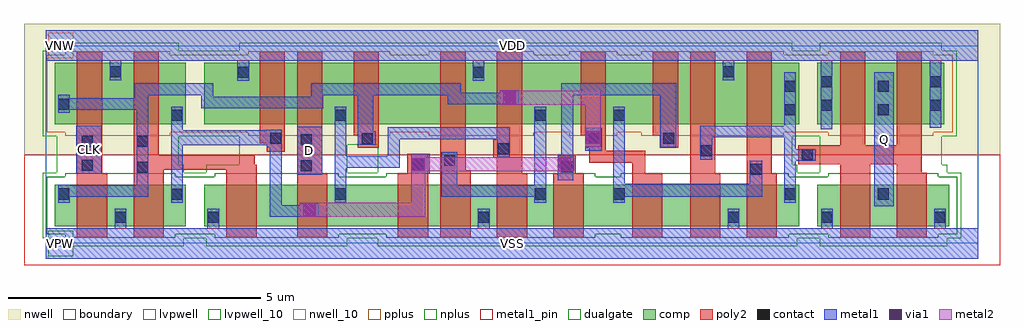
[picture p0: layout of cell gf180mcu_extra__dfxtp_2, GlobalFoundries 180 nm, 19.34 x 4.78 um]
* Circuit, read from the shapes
.subckt gf180mcu_extra__dfxtp_2 CLK D Q VDD VNW VSS
XM1 VSS CLK n1 VSUBS nfet_06v0 w=0.82u l=0.6u
XM2 n2 n1 VSS VSUBS nfet_06v0 w=0.82u l=0.6u
XM3 n3 n1 VSS VSUBS nfet_06v0 w=0.82u l=0.6u
XM4 n4 D n3 VSUBS nfet_06v0 w=0.82u l=0.6u
XM5 n5 n2 n4 VSUBS nfet_06v0 w=0.82u l=0.6u
XM6 VSS n6 n5 VSUBS nfet_06v0 w=0.82u l=0.6u
XM7 n6 n4 VSS VSUBS nfet_06v0 w=0.82u l=0.6u
XM8 n7 n2 n6 VSUBS nfet_06v0 w=0.82u l=0.6u
XM9 n8 n1 n7 VSUBS nfet_06v0 w=0.82u l=0.6u
XM10 VSS n9 n8 VSUBS nfet_06v0 w=0.82u l=0.6u
XM11 n9 n7 VSS VSUBS nfet_06v0 w=0.82u l=0.6u
XM12 Q n9 VSS VSUBS nfet_06v0 w=0.82u l=0.6u m=2
XM13 VDD CLK n1 VNW pfet_06v0 w=1.22u l=0.5u
XM14 n2 n1 VDD VNW pfet_06v0 w=1.22u l=0.5u
XM15 n10 n2 VDD VNW pfet_06v0 w=1.22u l=0.5u
XM16 n4 D n10 VNW pfet_06v0 w=1.22u l=0.5u
XM17 n11 n1 n4 VNW pfet_06v0 w=1.22u l=0.5u
XM18 VDD n6 n11 VNW pfet_06v0 w=1.22u l=0.5u
XM19 n6 n4 VDD VNW pfet_06v0 w=1.22u l=0.5u
XM20 n7 n1 n6 VNW pfet_06v0 w=1.22u l=0.5u
XM21 n12 n2 n7 VNW pfet_06v0 w=1.22u l=0.5u
XM22 VDD n9 n12 VNW pfet_06v0 w=1.22u l=0.5u
XM23 n9 n7 VDD VNW pfet_06v0 w=1.22u l=0.5u
XM24 Q n9 VDD VNW pfet_06v0 w=1.22u l=0.5u m=2
.ends

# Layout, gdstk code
import gdstk
lib = gdstk.Library(unit=1e-6, precision=1e-09)
def R(c, l, rs):  # rectangles x0, y0, x1, y1
    for r in rs: c.add(gdstk.rectangle(r[:2], r[2:], *l))
boundary = (0, 0)
nwell = (21, 0)
nwell_10 = (21, 10)
comp = (22, 0)
poly2 = (30, 0)
pplus = (31, 0)
nplus = (32, 0)
contact = (33, 0)
metal1 = (34, 0)
metal1_pin = (34, 10)
via1 = (35, 0)
metal2 = (36, 0)
dualgate = (55, 0)
lvpwell = (204, 0)
lvpwell_10 = (204, 10)

gf180mcu_extra__dfxtp_2 = lib.new_cell('gf180mcu_extra__dfxtp_2')
R(gf180mcu_extra__dfxtp_2, boundary, [(0,0,18.48,3.92)])
R(gf180mcu_extra__dfxtp_2, nwell, [(-0.43,1.76,18.91,4.35)])
R(gf180mcu_extra__dfxtp_2, nwell_10, [(0.05,3.67,0.55,4.17)])
R(gf180mcu_extra__dfxtp_2, comp, [(0.18,0.34,2.78,1.16), (3.14,0.34,14.93,1.16), (15.29,0.34,17.9,1.16), (0.18,2.36,2.78,3.58), (3.14,2.36,14.93,3.58), (15.29,2.36,17.81,3.58)])
R(gf180mcu_extra__dfxtp_2, poly2, [(0.62,0.12,1.22,1.38), (1.74,0.12,2.34,1.46), (3.58,0.12,4.18,1.46), (4.98,0.12,5.58,1.38), (6.98,0.12,7.58,1.38), (7.82,0.12,8.42,1.445), (8.94,0.12,9.54,1.38), (10.06,0.12,10.66,1.38), (11.62,0.12,12.22,1.38), (12.77,0.12,13.37,1.38), (13.89,0.12,14.49,1.385), (15.74,0.12,16.34,1.565), (16.86,0.12,17.46,1.4), (0.62,1.38,1.12,3.8), (4.98,1.38,5.48,3.8), (7.165,1.38,7.58,1.78), (8.94,1.38,9.44,1.695), (10.145,1.38,10.505,1.74), (11.62,1.38,11.88,1.595), (12.77,1.38,13.27,3.8), (13.89,1.385,14.39,3.8), (16.86,1.4,17.36,1.565), (7.82,1.445,8.32,3.8), (1.74,1.46,4.18,1.555), (1.74,1.555,4.145,1.745), (14.91,1.565,17.36,1.95), (10.775,1.595,11.88,1.835), (8.87,1.695,9.44,2.06), (1.74,1.745,2.24,3.8), (4.38,1.82,4.74,1.985), (10.775,1.835,11.1,1.9), (6.185,1.895,6.6,2.14), (10.695,1.9,11.1,2.14), (12.17,1.9,12.53,2.14), (15.74,1.95,16.24,3.8), (16.86,1.95,17.36,3.8), (4.24,1.985,4.74,3.8), (8.94,2.06,9.44,3.8), (6.1,2.14,6.6,3.8), (10.6,2.14,11.1,3.8), (12.03,2.14,12.53,3.8)])
R(gf180mcu_extra__dfxtp_2, pplus, [(0.39,2.13,2.47,2.2), (4.01,2.13,6.83,2.2), (7.59,2.13,9.67,2.2), (10.37,2.13,11.33,2.2), (11.8,2.13,14.62,2.2), (15.51,2.13,17.59,2.2), (0.02,2.2,17.97,3.74), (0.39,3.74,2.47,3.81), (4.01,3.74,6.83,3.81), (7.59,3.74,9.67,3.81), (10.37,3.74,11.33,3.81), (11.8,3.74,14.62,3.81), (15.51,3.74,17.59,3.81)])
R(gf180mcu_extra__dfxtp_2, nplus, [(0.39,0.11,2.57,0.18), (3.35,0.11,5.81,0.18), (6.75,0.11,10.89,0.18), (11.39,0.11,14.72,0.18), (15.51,0.11,17.69,0.18), (0.02,0.18,18.06,1.32), (0.39,1.32,2.57,1.39), (3.35,1.32,5.81,1.39), (6.75,1.32,10.89,1.39), (11.39,1.32,14.72,1.39), (15.51,1.32,17.69,1.39)])
R(gf180mcu_extra__dfxtp_2, contact, [(1.37,0.41,1.59,0.63), (3.21,0.41,3.43,0.63), (8.57,0.41,8.79,0.63), (13.52,0.41,13.74,0.63), (15.37,0.41,15.59,0.63), (17.61,0.41,17.83,0.63), (2.49,0.865,2.71,1.085), (0.25,0.87,0.47,1.09), (5.73,0.87,5.95,1.09), (9.69,0.87,9.91,1.09), (11.25,0.87,11.47,1.09), (14.64,0.87,14.86,1.09), (16.49,0.87,16.71,1.09), (13.965,1.36,14.185,1.58), (1.81,1.4,2.03,1.62), (10.215,1.41,10.435,1.63), (5.05,1.43,5.27,1.65), (0.71,1.44,0.93,1.66), (7.265,1.45,7.485,1.67), (7.895,1.54,8.115,1.76), (14.98,1.645,15.2,1.865), (12.98,1.725,13.2,1.945), (8.96,1.765,9.18,1.985), (0.71,1.91,0.93,2.13), (1.81,1.915,2.03,2.135), (5.05,1.945,5.27,2.165), (6.26,1.965,6.48,2.185), (4.45,1.97,4.67,2.19), (10.765,1.97,10.985,2.19), (12.24,1.97,12.46,2.19), (2.49,2.43,2.71,2.65), (5.73,2.43,5.95,2.65), (9.69,2.43,9.91,2.65), (11.25,2.43,11.47,2.65), (14.64,2.535,14.86,2.755), (16.49,2.535,16.71,2.755), (15.36,2.625,15.58,2.845), (17.52,2.625,17.74,2.845), (0.25,2.65,0.47,2.87), (14.64,3.005,14.86,3.225), (16.49,3.005,16.71,3.225), (15.36,3.095,15.58,3.315), (17.52,3.095,17.74,3.315), (3.805,3.285,4.025,3.505), (8.47,3.285,8.69,3.505), (1.27,3.29,1.49,3.51), (13.42,3.29,13.64,3.51)])
R(gf180mcu_extra__dfxtp_2, metal1, [(0,-0.3,18.48,0.3), (1.365,0.3,1.595,0.69), (3.205,0.3,3.435,0.69), (8.565,0.3,8.795,0.69), (13.515,0.3,13.745,0.69), (15.365,0.3,15.595,0.69), (17.605,0.3,17.835,0.69), (4.435,0.53,5.41,0.76), (16.42,0.735,16.805,3.39), (4.435,0.76,4.675,1.91), (5.03,0.76,5.41,0.8), (2.485,0.805,2.715,1.95), (0.245,0.81,0.475,0.92), (5.725,0.81,5.955,1.5), (9.685,0.81,9.915,0.925), (11.245,0.81,11.475,0.92), (14.635,0.81,14.865,1.64), (0.245,0.92,2.035,1.15), (11.245,0.92,14.2,1.18), (7.84,0.925,9.915,1.155), (0.245,1.15,0.475,1.16), (1.805,1.15,2.035,2.645), (7.84,1.155,8.16,1.81), (9.685,1.155,9.915,2.71), (11.245,1.18,11.475,2.71), (13.955,1.18,14.2,1.64), (10.145,1.255,10.45,1.76), (4.98,1.365,5.48,2.315), (0.61,1.38,1.11,2.33), (7.245,1.38,7.61,1.78), (5.725,1.5,7.015,1.73), (14.635,1.64,15.26,1.87), (12.975,1.66,13.205,2.105), (8.95,1.705,9.195,2.065), (5.725,1.73,5.955,2.71), (6.775,1.73,7.015,2.065), (10.22,1.76,10.45,2.94), (10.695,1.84,11.015,2.295), (14.635,1.87,14.865,2.105), (4.38,1.91,4.675,1.95), (12.18,1.91,12.495,2.94), (2.485,1.95,4.675,2.245), (6.185,1.96,6.545,2.225), (6.775,2.065,9.195,2.3), (12.975,2.105,14.865,2.335), (6.185,2.225,6.49,2.94), (2.485,2.245,2.715,2.71), (4.38,2.245,4.675,2.25), (15.355,2.26,15.585,3.62), (17.515,2.29,17.745,3.62), (14.635,2.335,14.865,3.39), (0.245,2.59,0.475,2.645), (0.245,2.645,2.035,2.875), (3.085,2.675,5.495,2.905), (7.965,2.76,9.375,2.94), (0.245,2.875,0.475,2.95), (1.765,2.875,2.035,2.94), (3.085,2.905,3.325,2.94), (5.265,2.905,5.495,2.94), (1.765,2.94,3.325,3.17), (5.265,2.94,9.375,2.99), (10.22,2.94,12.495,3.17), (5.265,2.99,8.22,3.17), (8.995,2.99,9.375,3.025), (3.8,3.225,4.03,3.62), (8.465,3.225,8.695,3.62), (1.265,3.23,1.495,3.62), (13.415,3.23,13.645,3.62), (0,3.62,18.48,4.22)])
R(gf180mcu_extra__dfxtp_2, metal1_pin, [(0,-0.3,18.48,0.3), (16.42,0.735,16.805,3.39), (4.98,1.365,5.48,2.315), (0.61,1.38,1.11,2.33), (0,3.62,18.48,4.22)])
R(gf180mcu_extra__dfxtp_2, via1, [(5.09,0.54,5.35,0.8), (7.255,1.44,7.515,1.7), (10.155,1.44,10.415,1.7), (10.715,1.975,10.975,2.235), (9.055,2.76,9.315,3.02)])
R(gf180mcu_extra__dfxtp_2, metal2, [(5.03,0.53,7.525,0.81), (7.245,0.81,7.525,1.43), (7.245,1.43,10.475,1.71), (7.245,1.71,7.525,1.76), (10.695,1.915,10.995,2.745), (8.995,2.745,10.995,3.025), (8.995,3.025,9.375,3.035)])
R(gf180mcu_extra__dfxtp_2, dualgate, [(0.22,-0.06,2.74,0.1), (3.18,-0.06,5.98,0.1), (6.58,-0.06,14.89,0.1), (15.34,-0.06,17.86,0.1), (-0.06,0.1,18.14,1.4), (0.22,1.4,2.74,1.56), (3.18,1.4,5.98,1.56), (6.58,1.4,14.89,1.56), (15.34,1.4,17.86,1.56), (0.22,1.56,2.64,2.12), (3.84,1.56,5.98,1.96), (6.58,1.56,14.79,1.96), (15.34,1.56,17.76,2.12), (3.84,1.96,14.79,2.12), (-0.06,2.12,18.05,3.82), (0.22,3.82,2.64,3.98), (3.84,3.82,14.79,3.98), (15.34,3.82,17.76,3.98)])
R(gf180mcu_extra__dfxtp_2, lvpwell, [(-0.43,-0.43,18.91,1.76)])
R(gf180mcu_extra__dfxtp_2, lvpwell_10, [(0.05,-0.25,0.55,0.25)])
gf180mcu_extra__dfxtp_2.add(gdstk.Label('VDD', (9.24,3.92), layer=34, texttype=10))
gf180mcu_extra__dfxtp_2.add(gdstk.Label('VNW', (0.3,3.92), layer=21, texttype=10))
gf180mcu_extra__dfxtp_2.add(gdstk.Label('VPW', (0.3,0), layer=204, texttype=10))
gf180mcu_extra__dfxtp_2.add(gdstk.Label('VSS', (9.24,0), layer=34, texttype=10))
gf180mcu_extra__dfxtp_2.add(gdstk.Label('Q', (16.612,2.062), layer=34, texttype=10))
gf180mcu_extra__dfxtp_2.add(gdstk.Label('D', (5.23,1.84), layer=34, texttype=10))
gf180mcu_extra__dfxtp_2.add(gdstk.Label('CLK', (0.86,1.855), layer=34, texttype=10))

lib.write_gds('gf180mcu_extra__dfxtp_2.gds')
